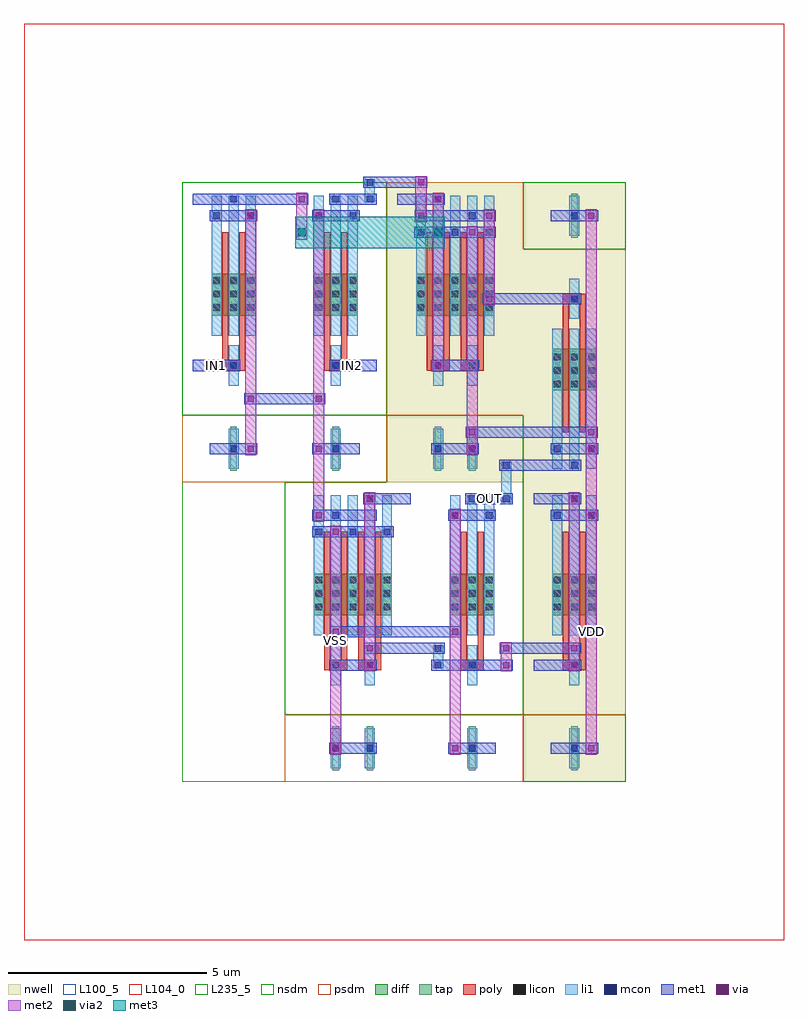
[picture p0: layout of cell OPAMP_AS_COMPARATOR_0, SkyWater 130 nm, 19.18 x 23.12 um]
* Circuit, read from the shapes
.subckt OPAMP_AS_COMPARATOR_0 IN1 IN2 OUT VDD VSS
XM1 n1 IN1 VSS VSS sky130_fd_pr__nfet_01v8 w=1.05 l=0.15 m=2
XM2 VSS n2 VSS VSS sky130_fd_pr__nfet_01v8 w=1.05 l=0.15 m=2
XM3 n3 IN2 VSS VSS sky130_fd_pr__nfet_01v8 w=1.05 l=0.15 m=2
XM4 n2 n2 VSS VSS sky130_fd_pr__nfet_01v8 w=1.05 l=0.15 m=2
XM5 OUT n2 VSS VSS sky130_fd_pr__nfet_01v8 w=1.05 l=0.15 m=2
XM6 n1 n1 VDD VDD sky130_fd_pr__pfet_01v8 w=1.05 l=0.15 m=2
XM7 n3 n1 VDD VDD sky130_fd_pr__pfet_01v8 w=1.05 l=0.15 m=2
XM8 n2 n2 VDD VDD sky130_fd_pr__pfet_01v8 w=1.05 l=0.15 m=2
XM9 OUT n3 VDD VDD sky130_fd_pr__pfet_01v8 w=1.05 l=0.15 m=2
.ends

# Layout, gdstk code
from math import pi, radians
import gdstk
lib = gdstk.Library(unit=1e-6, precision=1e-09)
def R(c, l, rs):  # rectangles x0, y0, x1, y1
    for r in rs: c.add(gdstk.rectangle(r[:2], r[2:], *l))
def A(c, l, x, y, w, h, nx, ny, dx, dy):  # array of equal rectangles
    R(c, l, [(x+i*dx, y+j*dy, x+i*dx+w, y+j*dy+h) for i in range(nx) for j in range(ny)])
def P(c, l, *ps):  # polygons
    for p in ps: c.add(gdstk.Polygon(p, *l))
nwell = (64, 20)
diff = (65, 20)
tap = (65, 44)
poly = (66, 20)
licon = (66, 44)
li1 = (67, 20)
mcon = (67, 44)
met1 = (68, 20)
via = (68, 44)
met2 = (69, 20)
via2 = (69, 44)
met3 = (70, 20)
nsdm = (93, 44)
psdm = (94, 20)
L100_5 = (100, 5)
L104_0 = (104, 0)
L235_5 = (235, 5)

scm_nmos_43308780_x1_y1_ = lib.new_cell('SCM_NMOS_43308780_X1_Y1_1678856068_1678856067')
R(scm_nmos_43308780_x1_y1_, diff, [(0.735,2.31,2.705,3.36)])
R(scm_nmos_43308780_x1_y1_, tap, [(1.205,6.16,1.375,7.28), (2.065,6.16,2.235,7.28)])
A(scm_nmos_43308780_x1_y1_, poly, 1, 1.26, 0.15, 3.36, 4, 1, 0.43, 0)
R(scm_nmos_43308780_x1_y1_, poly, [(1,4.485,1.58,4.755), (1.86,4.485,2.44,4.755)])
A(scm_nmos_43308780_x1_y1_, licon, 0.775, 2.39, 0.17, 0.17, 3, 3, 0.43, 0.34)
A(scm_nmos_43308780_x1_y1_, licon, 1.635, 2.39, 0.17, 0.17, 3, 3, 0.43, 0.34)
R(scm_nmos_43308780_x1_y1_, licon, [(1.205,4.535,1.375,4.705), (2.065,4.535,2.235,4.705), (1.205,6.635,1.375,6.805), (2.065,6.635,2.235,6.805)])
A(scm_nmos_43308780_x1_y1_, li1, 0.735, 0.335, 0.25, 3.53, 5, 1, 0.43, 0)
R(scm_nmos_43308780_x1_y1_, li1, [(1.165,4.115,1.415,5.125), (2.025,4.115,2.275,5.125), (1.165,6.215,1.415,7.225), (2.025,6.215,2.275,7.225)])
A(scm_nmos_43308780_x1_y1_, mcon, 0.775, 1.175, 0.17, 0.17, 3, 1, 0.86, 0)
R(scm_nmos_43308780_x1_y1_, mcon, [(1.205,0.335,1.375,0.505), (2.065,0.755,2.235,0.925), (1.205,4.535,1.375,4.705), (2.065,4.535,2.235,4.705), (1.205,6.635,1.375,6.805), (2.065,6.635,2.235,6.805)])
R(scm_nmos_43308780_x1_y1_, met1, [(0.26,0.28,1.46,0.56), (1.12,0.7,2.32,0.98), (0.69,1.12,2.75,1.4), (1.12,4.48,2.32,4.76), (1.12,6.58,2.32,6.86)])
R(scm_nmos_43308780_x1_y1_, via, [(1.215,0.345,1.365,0.495), (2.075,1.185,2.225,1.335), (1.215,4.545,1.365,4.695), (2.075,6.645,2.225,6.795)])
R(scm_nmos_43308780_x1_y1_, met2, [(1.15,0.26,1.43,4.78), (2.01,1.1,2.29,6.88)])
R(scm_nmos_43308780_x1_y1_, nsdm, [(0,0,3.44,5.88)])
R(scm_nmos_43308780_x1_y1_, psdm, [(0,5.88,3.44,7.56)])
R(scm_nmos_43308780_x1_y1_, L100_5, [(0,0,3.44,7.56)])

nmos_s_54487678_x1_y1_16 = lib.new_cell('NMOS_S_54487678_X1_Y1_1678856067_1678856067')
R(nmos_s_54487678_x1_y1_16, diff, [(0.735,2.31,1.845,3.36)])
R(nmos_s_54487678_x1_y1_16, tap, [(1.205,6.16,1.375,7.28)])
R(nmos_s_54487678_x1_y1_16, poly, [(1,1.26,1.15,4.62), (1.43,1.26,1.58,4.62), (1,4.485,1.58,4.755)])
A(nmos_s_54487678_x1_y1_16, licon, 0.775, 2.39, 0.17, 0.17, 3, 3, 0.43, 0.34)
R(nmos_s_54487678_x1_y1_16, licon, [(1.205,4.535,1.375,4.705), (1.205,6.635,1.375,6.805)])
A(nmos_s_54487678_x1_y1_16, li1, 0.735, 0.335, 0.25, 3.53, 3, 1, 0.43, 0)
R(nmos_s_54487678_x1_y1_16, li1, [(1.165,4.115,1.415,5.125), (1.165,6.215,1.415,7.225)])
R(nmos_s_54487678_x1_y1_16, mcon, [(1.205,0.335,1.375,0.505), (0.775,0.755,0.945,0.925), (1.635,0.755,1.805,0.925), (1.205,4.535,1.375,4.705), (1.205,6.635,1.375,6.805)])
R(nmos_s_54487678_x1_y1_16, met1, [(0.26,0.28,1.46,0.56), (0.69,0.7,1.89,0.98), (0.26,4.48,1.46,4.76), (0.69,6.58,1.89,6.86)])
R(nmos_s_54487678_x1_y1_16, via, [(1.645,0.765,1.795,0.915), (1.645,6.645,1.795,6.795)])
R(nmos_s_54487678_x1_y1_16, met2, [(1.58,0.68,1.86,6.88)])
R(nmos_s_54487678_x1_y1_16, nsdm, [(0,0,2.58,5.88)])
R(nmos_s_54487678_x1_y1_16, psdm, [(0,5.88,2.58,7.56)])
R(nmos_s_54487678_x1_y1_16, L100_5, [(0,0,2.58,7.56)])

cmb_nmos_2_43145097_0_0_ = lib.new_cell('CMB_NMOS_2_43145097_0_0_1678856067')
R(cmb_nmos_2_43145097_0_0_, li1, [(2.025,4.115,2.275,4.285), (2.025,4.115,2.275,4.285), (2.025,4.2,2.275,4.62), (2.025,4.535,2.275,4.705), (2.025,4.535,2.275,4.705)])
R(cmb_nmos_2_43145097_0_0_, mcon, [(2.065,4.115,2.235,4.285), (2.065,4.115,2.235,4.285), (2.065,4.535,2.235,4.705), (2.065,4.535,2.235,4.705)])
R(cmb_nmos_2_43145097_0_0_, met1, [(1.56,3.64,1.88,3.92), (1.56,3.64,1.88,3.92), (1.72,3.64,4.73,3.92), (4.57,3.64,4.89,3.92), (4.57,3.64,4.89,3.92), (1.98,4.06,2.32,4.34), (1.98,4.06,2.32,4.34), (2.15,4.06,3.87,4.34), (3.71,4.06,4.03,4.34), (3.71,4.06,4.03,4.34), (1.29,4.48,2.15,4.76), (1.98,4.48,2.32,4.76), (1.98,4.48,2.32,4.76)])
P(cmb_nmos_2_43145097_0_0_, met1, [(0,0),(0,0),(0,0),(0,0)],
  [(0,0),(0,0),(0,0),(0,0)],
  [(0,0),(0,0),(0,0),(0,0)])
R(cmb_nmos_2_43145097_0_0_, via, [(1.645,3.705,1.795,3.855), (1.645,3.705,1.795,3.855), (4.655,3.705,4.805,3.855), (4.655,3.705,4.805,3.855), (3.795,4.125,3.945,4.275), (3.795,4.125,3.945,4.275)])
R(cmb_nmos_2_43145097_0_0_, met2, [(1.58,3.62,1.86,3.94), (1.58,3.62,1.86,3.94), (4.59,3.62,4.87,3.94), (4.59,3.62,4.87,3.94), (3.73,4.04,4.01,4.36), (3.73,4.04,4.01,4.36)])
P(cmb_nmos_2_43145097_0_0_, met2, [(0,0),(0,0),(0,0),(0,0)],
  [(0,0),(0,0),(0,0),(0,0)],
  [(0,0),(0,0),(0,0),(0,0)])
R(cmb_nmos_2_43145097_0_0_, L235_5, [(0,0,6.02,7.56)])
cmb_nmos_2_43145097_0_0_.add(gdstk.Reference(scm_nmos_43308780_x1_y1_, (2.58,0)))
cmb_nmos_2_43145097_0_0_.add(gdstk.Reference(nmos_s_54487678_x1_y1_16, (0,0)))

scm_pmos_7675836_x1_y1_1 = lib.new_cell('SCM_PMOS_7675836_X1_Y1_1678856071')
R(scm_pmos_7675836_x1_y1_1, nwell, [(0,0,3.44,7.56)])
R(scm_pmos_7675836_x1_y1_1, diff, [(0.735,2.31,2.705,3.36)])
R(scm_pmos_7675836_x1_y1_1, tap, [(1.205,6.16,1.375,7.28), (2.065,6.16,2.235,7.28)])
A(scm_pmos_7675836_x1_y1_1, poly, 1, 1.26, 0.15, 3.36, 4, 1, 0.43, 0)
R(scm_pmos_7675836_x1_y1_1, poly, [(1,4.485,1.58,4.755), (1.86,4.485,2.44,4.755)])
A(scm_pmos_7675836_x1_y1_1, licon, 0.775, 2.39, 0.17, 0.17, 3, 3, 0.43, 0.34)
A(scm_pmos_7675836_x1_y1_1, licon, 1.635, 2.39, 0.17, 0.17, 3, 3, 0.43, 0.34)
R(scm_pmos_7675836_x1_y1_1, licon, [(1.205,4.535,1.375,4.705), (2.065,4.535,2.235,4.705), (1.205,6.635,1.375,6.805), (2.065,6.635,2.235,6.805)])
A(scm_pmos_7675836_x1_y1_1, li1, 0.735, 0.335, 0.25, 3.53, 5, 1, 0.43, 0)
R(scm_pmos_7675836_x1_y1_1, li1, [(1.165,4.115,1.415,5.125), (2.025,4.115,2.275,5.125), (1.165,6.215,1.415,7.225), (2.025,6.215,2.275,7.225)])
A(scm_pmos_7675836_x1_y1_1, mcon, 0.775, 1.175, 0.17, 0.17, 3, 1, 0.86, 0)
R(scm_pmos_7675836_x1_y1_1, mcon, [(1.205,0.335,1.375,0.505), (2.065,0.755,2.235,0.925), (1.205,4.535,1.375,4.705), (2.065,4.535,2.235,4.705), (1.205,6.635,1.375,6.805), (2.065,6.635,2.235,6.805)])
R(scm_pmos_7675836_x1_y1_1, met1, [(0.26,0.28,1.46,0.56), (1.12,0.7,2.32,0.98), (0.69,1.12,2.75,1.4), (1.12,4.48,2.32,4.76), (1.12,6.58,2.32,6.86)])
R(scm_pmos_7675836_x1_y1_1, via, [(1.215,0.345,1.365,0.495), (2.075,1.185,2.225,1.335), (1.215,4.545,1.365,4.695), (2.075,6.645,2.225,6.795)])
R(scm_pmos_7675836_x1_y1_1, met2, [(1.15,0.26,1.43,4.78), (2.01,1.1,2.29,6.88)])
R(scm_pmos_7675836_x1_y1_1, nsdm, [(0,5.88,3.44,7.56)])
R(scm_pmos_7675836_x1_y1_1, psdm, [(0,0,3.44,5.88)])
R(scm_pmos_7675836_x1_y1_1, L100_5, [(0,0,3.44,7.56)])

dcl_pmos_s_36446492_x1_y = lib.new_cell('DCL_PMOS_S_36446492_X1_Y1_1678856068')
R(dcl_pmos_s_36446492_x1_y, nwell, [(0,0,2.58,7.56)])
R(dcl_pmos_s_36446492_x1_y, diff, [(0.735,2.31,1.845,3.36)])
R(dcl_pmos_s_36446492_x1_y, tap, [(1.205,6.16,1.375,7.28)])
R(dcl_pmos_s_36446492_x1_y, poly, [(1,1.26,1.15,4.62), (1.43,1.26,1.58,4.62), (1,4.485,1.58,4.755)])
A(dcl_pmos_s_36446492_x1_y, licon, 0.775, 2.39, 0.17, 0.17, 3, 3, 0.43, 0.34)
R(dcl_pmos_s_36446492_x1_y, licon, [(1.205,4.535,1.375,4.705), (1.205,6.635,1.375,6.805)])
A(dcl_pmos_s_36446492_x1_y, li1, 0.735, 0.335, 0.25, 3.53, 3, 1, 0.43, 0)
R(dcl_pmos_s_36446492_x1_y, li1, [(1.165,4.115,1.415,5.125), (1.165,6.215,1.415,7.225)])
R(dcl_pmos_s_36446492_x1_y, mcon, [(1.205,0.335,1.375,0.505), (0.775,0.755,0.945,0.925), (1.635,0.755,1.805,0.925), (1.205,4.535,1.375,4.705), (1.205,6.635,1.375,6.805)])
R(dcl_pmos_s_36446492_x1_y, met1, [(0.26,0.28,1.46,0.56), (0.69,0.7,1.89,0.98), (0.26,4.48,1.46,4.76), (0.69,6.58,1.89,6.86)])
R(dcl_pmos_s_36446492_x1_y, via, [(1.215,0.345,1.365,0.495), (1.645,0.765,1.795,0.915), (1.215,4.545,1.365,4.695), (1.645,6.645,1.795,6.795)])
R(dcl_pmos_s_36446492_x1_y, met2, [(1.15,0.26,1.43,4.78), (1.58,0.68,1.86,6.88)])
R(dcl_pmos_s_36446492_x1_y, nsdm, [(0,5.88,2.58,7.56)])
R(dcl_pmos_s_36446492_x1_y, psdm, [(0,0,2.58,5.88)])
R(dcl_pmos_s_36446492_x1_y, L100_5, [(0,0,2.58,7.56)])

c_nmos_s_54487678_x1_y1_16 = lib.new_cell('NMOS_S_54487678_X1_Y1_1678856069')
R(c_nmos_s_54487678_x1_y1_16, diff, [(0.735,2.31,1.845,3.36)])
R(c_nmos_s_54487678_x1_y1_16, tap, [(1.205,6.16,1.375,7.28)])
R(c_nmos_s_54487678_x1_y1_16, poly, [(1,1.26,1.15,4.62), (1.43,1.26,1.58,4.62), (1,4.485,1.58,4.755)])
A(c_nmos_s_54487678_x1_y1_16, licon, 0.775, 2.39, 0.17, 0.17, 3, 3, 0.43, 0.34)
R(c_nmos_s_54487678_x1_y1_16, licon, [(1.205,4.535,1.375,4.705), (1.205,6.635,1.375,6.805)])
A(c_nmos_s_54487678_x1_y1_16, li1, 0.735, 0.335, 0.25, 3.53, 3, 1, 0.43, 0)
R(c_nmos_s_54487678_x1_y1_16, li1, [(1.165,4.115,1.415,5.125), (1.165,6.215,1.415,7.225)])
R(c_nmos_s_54487678_x1_y1_16, mcon, [(1.205,0.335,1.375,0.505), (0.775,0.755,0.945,0.925), (1.635,0.755,1.805,0.925), (1.205,4.535,1.375,4.705), (1.205,6.635,1.375,6.805)])
R(c_nmos_s_54487678_x1_y1_16, met1, [(0.26,0.28,1.46,0.56), (0.69,0.7,1.89,0.98), (0.26,4.48,1.46,4.76), (0.69,6.58,1.89,6.86)])
R(c_nmos_s_54487678_x1_y1_16, via, [(1.645,0.765,1.795,0.915), (1.645,6.645,1.795,6.795)])
R(c_nmos_s_54487678_x1_y1_16, met2, [(1.58,0.68,1.86,6.88)])
R(c_nmos_s_54487678_x1_y1_16, nsdm, [(0,0,2.58,5.88)])
R(c_nmos_s_54487678_x1_y1_16, psdm, [(0,5.88,2.58,7.56)])
R(c_nmos_s_54487678_x1_y1_16, L100_5, [(0,0,2.58,7.56)])

pmos_s_87189516_x1_y1_16 = lib.new_cell('PMOS_S_87189516_X1_Y1_1678856070')
R(pmos_s_87189516_x1_y1_16, nwell, [(0,0,2.58,7.56)])
R(pmos_s_87189516_x1_y1_16, diff, [(0.735,2.31,1.845,3.36)])
R(pmos_s_87189516_x1_y1_16, tap, [(1.205,6.16,1.375,7.28)])
R(pmos_s_87189516_x1_y1_16, poly, [(1,1.26,1.15,4.62), (1.43,1.26,1.58,4.62), (1,4.485,1.58,4.755)])
A(pmos_s_87189516_x1_y1_16, licon, 0.775, 2.39, 0.17, 0.17, 3, 3, 0.43, 0.34)
R(pmos_s_87189516_x1_y1_16, licon, [(1.205,4.535,1.375,4.705), (1.205,6.635,1.375,6.805)])
A(pmos_s_87189516_x1_y1_16, li1, 0.735, 0.335, 0.25, 3.53, 3, 1, 0.43, 0)
R(pmos_s_87189516_x1_y1_16, li1, [(1.165,4.115,1.415,5.125), (1.165,6.215,1.415,7.225)])
R(pmos_s_87189516_x1_y1_16, mcon, [(1.205,0.335,1.375,0.505), (0.775,0.755,0.945,0.925), (1.635,0.755,1.805,0.925), (1.205,4.535,1.375,4.705), (1.205,6.635,1.375,6.805)])
R(pmos_s_87189516_x1_y1_16, met1, [(0.26,0.28,1.46,0.56), (0.69,0.7,1.89,0.98), (0.26,4.48,1.46,4.76), (0.69,6.58,1.89,6.86)])
R(pmos_s_87189516_x1_y1_16, via, [(1.645,0.765,1.795,0.915), (1.645,6.645,1.795,6.795)])
R(pmos_s_87189516_x1_y1_16, met2, [(1.58,0.68,1.86,6.88)])
R(pmos_s_87189516_x1_y1_16, nsdm, [(0,5.88,2.58,7.56)])
R(pmos_s_87189516_x1_y1_16, psdm, [(0,0,2.58,5.88)])
R(pmos_s_87189516_x1_y1_16, L100_5, [(0,0,2.58,7.56)])

opamp_as_comparator_0 = lib.new_cell('OPAMP_AS_COMPARATOR_0')
R(opamp_as_comparator_0, li1, [(8.045,7.055,8.295,7.225), (8.045,7.055,8.295,7.225), (8.045,7.14,8.295,7.98), (8.045,7.895,8.295,8.065), (8.045,7.895,8.295,8.065), (4.605,14.615,4.855,14.785), (4.605,14.615,4.855,14.785), (4.605,14.615,4.855,14.785), (4.605,14.615,4.855,14.785), (4.605,14.7,4.855,15.12), (4.605,15.035,4.855,15.205), (4.605,15.035,4.855,15.205), (4.605,15.035,4.855,15.205), (4.605,15.035,4.855,15.205)])
P(opamp_as_comparator_0, li1, [(0,0),(0,0),(0,0),(0,0)])
R(opamp_as_comparator_0, mcon, [(8.085,7.055,8.255,7.225), (8.085,7.055,8.255,7.225), (8.085,7.895,8.255,8.065), (8.085,7.895,8.255,8.065), (4.645,14.615,4.815,14.785), (4.645,14.615,4.815,14.785), (4.645,14.615,4.815,14.785), (4.645,14.615,4.815,14.785), (4.645,15.035,4.815,15.205), (4.645,15.035,4.815,15.205), (4.645,15.035,4.815,15.205), (4.645,15.035,4.815,15.205)])
R(opamp_as_comparator_0, met1, [(8.01,2.8,8.33,3.08), (8.01,2.8,8.33,3.08), (8.01,3.22,8.33,3.5), (8.01,3.22,8.33,3.5), (8.17,3.22,9.89,3.5), (9.73,3.22,10.05,3.5), (9.73,3.22,10.05,3.5), (3.28,6.58,3.6,6.86), (3.28,6.58,3.6,6.86), (3.28,6.58,3.6,6.86), (3.28,6.58,3.6,6.86), (3.44,6.58,3.87,6.86), (8,7,8.34,7.28), (8,7,8.34,7.28), (8,7.84,8.34,8.12), (8,7.84,8.34,8.12), (8.17,7.84,9.03,8.12), (7.15,8.68,7.47,8.96), (7.15,8.68,7.47,8.96), (7.31,8.68,10.32,8.96), (10.16,8.68,10.48,8.96), (10.16,8.68,10.48,8.96), (1.56,9.52,1.88,9.8), (1.56,9.52,1.88,9.8), (1.72,9.52,3.44,9.8), (3.28,9.52,3.6,9.8), (3.28,9.52,3.6,9.8), (7.58,12.04,7.9,12.32), (7.58,12.04,7.9,12.32), (7.74,12.04,9.03,12.32), (5.86,14.14,6.18,14.42), (5.86,14.14,6.18,14.42), (5.86,14.14,6.18,14.42), (5.86,14.14,6.18,14.42), (6.02,14.14,6.45,14.42), (7.31,14.14,7.74,14.42), (7.58,14.14,7.9,14.42), (7.58,14.14,7.9,14.42), (1.29,14.56,3.01,14.84), (2.85,14.56,3.17,14.84), (2.85,14.56,3.17,14.84), (4.56,14.56,4.9,14.84), (4.56,14.56,4.9,14.84), (4.56,14.56,4.9,14.84), (4.56,14.56,4.9,14.84), (4.56,14.98,4.9,15.26), (4.56,14.98,4.9,15.26), (4.56,14.98,4.9,15.26), (4.56,14.98,4.9,15.26), (4.73,14.98,6.02,15.26), (5.86,14.98,6.18,15.26), (5.86,14.98,6.18,15.26), (5.86,14.98,6.18,15.26), (5.86,14.98,6.18,15.26)])
P(opamp_as_comparator_0, met1, [(0,0),(0,0),(0,0),(0,0)],
  [(0,0),(0,0),(0,0),(0,0)],
  [(0,0),(0,0),(0,0),(0,0)],
  [(0,0),(0,0),(0,0),(0,0)],
  [(0,0),(0,0),(0,0),(0,0)],
  [(0,0),(0,0),(0,0),(0,0)],
  [(0,0),(0,0),(0,0),(0,0)],
  [(0,0),(0,0),(0,0),(0,0)],
  [(0,0),(0,0),(0,0),(0,0)],
  [(0,0),(0,0),(0,0),(0,0)],
  [(0,0),(0,0),(0,0),(0,0)],
  [(0,0),(0,0),(0,0),(0,0)],
  [(0,0),(0,0),(0,0),(0,0)],
  [(0,0),(0,0),(0,0),(0,0)],
  [(0,0),(0,0),(0,0),(0,0)],
  [(0,0),(0,0),(0,0),(0,0)])
R(opamp_as_comparator_0, via, [(8.095,2.865,8.245,3.015), (8.095,2.865,8.245,3.015), (8.095,3.285,8.245,3.435), (8.095,3.285,8.245,3.435), (9.815,3.285,9.965,3.435), (9.815,3.285,9.965,3.435), (3.365,6.645,3.515,6.795), (3.365,6.645,3.515,6.795), (3.365,6.645,3.515,6.795), (3.365,6.645,3.515,6.795), (7.235,8.745,7.385,8.895), (7.235,8.745,7.385,8.895), (10.245,8.745,10.395,8.895), (10.245,8.745,10.395,8.895), (1.645,9.585,1.795,9.735), (1.645,9.585,1.795,9.735), (3.365,9.585,3.515,9.735), (3.365,9.585,3.515,9.735), (7.665,12.105,7.815,12.255), (7.665,12.105,7.815,12.255), (5.945,14.205,6.095,14.355), (5.945,14.205,6.095,14.355), (5.945,14.205,6.095,14.355), (5.945,14.205,6.095,14.355), (7.665,14.205,7.815,14.355), (7.665,14.205,7.815,14.355), (2.935,14.625,3.085,14.775), (2.935,14.625,3.085,14.775), (5.945,15.045,6.095,15.195), (5.945,15.045,6.095,15.195), (5.945,15.045,6.095,15.195), (5.945,15.045,6.095,15.195)])
R(opamp_as_comparator_0, met2, [(8.03,2.78,8.31,3.1), (8.03,2.78,8.31,3.1), (8.03,2.94,8.31,3.36), (8.03,3.2,8.31,3.52), (8.03,3.2,8.31,3.52), (9.75,3.2,10.03,3.52), (9.75,3.2,10.03,3.52), (3.3,6.56,3.58,6.88), (3.3,6.56,3.58,6.88), (3.3,6.56,3.58,6.88), (3.3,6.56,3.58,6.88), (3.3,6.72,3.58,8.4), (10.18,6.72,10.46,8.4), (7.17,8.66,7.45,8.98), (7.17,8.66,7.45,8.98), (10.18,8.66,10.46,8.98), (10.18,8.66,10.46,8.98), (1.58,9.5,1.86,9.82), (1.58,9.5,1.86,9.82), (3.3,9.5,3.58,9.82), (3.3,9.5,3.58,9.82), (7.6,12.02,7.88,12.34), (7.6,12.02,7.88,12.34), (7.6,12.18,7.88,14.28), (2.87,13.675,3.15,14.045), (2.87,13.675,3.15,14.045), (6.31,13.675,6.59,14.045), (6.31,13.675,6.59,14.045), (2.87,13.86,3.15,14.7), (5.88,14.12,6.16,14.44), (5.88,14.12,6.16,14.44), (5.88,14.12,6.16,14.44), (5.88,14.12,6.16,14.44), (7.6,14.12,7.88,14.44), (7.6,14.12,7.88,14.44), (5.88,14.28,6.16,15.12), (2.87,14.54,3.15,14.86), (2.87,14.54,3.15,14.86), (5.88,14.96,6.16,15.28), (5.88,14.96,6.16,15.28), (5.88,14.96,6.16,15.28), (5.88,14.96,6.16,15.28)])
P(opamp_as_comparator_0, met2, [(0,0),(0,0),(0,0),(0,0)],
  [(0,0),(0,0),(0,0),(0,0)],
  [(0,0),(0,0),(0,0),(0,0)],
  [(0,0),(0,0),(0,0),(0,0)],
  [(0,0),(0,0),(0,0),(0,0)],
  [(0,0),(0,0),(0,0),(0,0)],
  [(0,0),(0,0),(0,0),(0,0)],
  [(0,0),(0,0),(0,0),(0,0)],
  [(0,0),(0,0),(0,0),(0,0)],
  [(0,0),(0,0),(0,0),(0,0)],
  [(0,0),(0,0),(0,0),(0,0)],
  [(0,0),(0,0),(0,0),(0,0)],
  [(0,0),(0,0),(0,0),(0,0)],
  [(0,0),(0,0),(0,0),(0,0)],
  [(0,0),(0,0),(0,0),(0,0)])
R(opamp_as_comparator_0, via2, [(2.91,13.76,3.11,13.96), (2.91,13.76,3.11,13.96), (6.35,13.76,6.55,13.96), (6.35,13.76,6.55,13.96)])
R(opamp_as_comparator_0, met3, [(2.845,13.46,3.175,14.26), (2.845,13.46,3.175,14.26), (3.01,13.46,6.45,14.26), (6.285,13.46,6.615,14.26), (6.285,13.46,6.615,14.26)])
R(opamp_as_comparator_0, L104_0, [(-4,-4,15.18,19.12)])
R(opamp_as_comparator_0, L235_5, [(0,0,11.18,15.12)])
opamp_as_comparator_0.add(gdstk.Reference(cmb_nmos_2_43145097_0_0_, (8.6,7.56), rotation=pi))
opamp_as_comparator_0.add(gdstk.Reference(scm_pmos_7675836_x1_y1_1, (5.16,15.12), x_reflection=True))
opamp_as_comparator_0.add(gdstk.Reference(dcl_pmos_s_36446492_x1_y, (8.6,7.56), x_reflection=True))
opamp_as_comparator_0.add(gdstk.Reference(c_nmos_s_54487678_x1_y1_16, (0,15.12), x_reflection=True))
opamp_as_comparator_0.add(gdstk.Reference(c_nmos_s_54487678_x1_y1_16, (5.16,15.12), rotation=pi))
opamp_as_comparator_0.add(gdstk.Reference(pmos_s_87189516_x1_y1_16, (8.6,7.56)))
opamp_as_comparator_0.add(gdstk.Label('OUT', (7.74,7.14), layer=68, texttype=5))
opamp_as_comparator_0.add(gdstk.Label('VSS', (3.87,3.57), layer=69, texttype=5))
opamp_as_comparator_0.add(gdstk.Label('VDD', (10.32,3.78), layer=69, texttype=5))
opamp_as_comparator_0.add(gdstk.Label('IN1', (0.86,10.5), layer=68, texttype=5))
opamp_as_comparator_0.add(gdstk.Label('IN2', (4.3,10.5), layer=68, texttype=5))

lib.write_gds('OPAMP_AS_COMPARATOR_0.gds')
